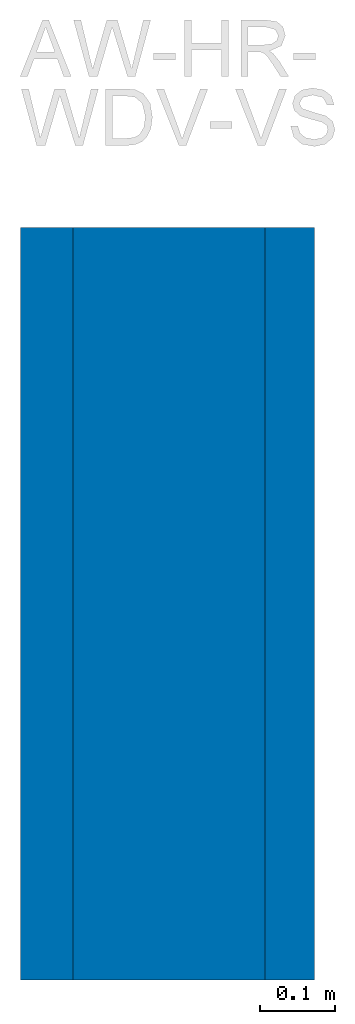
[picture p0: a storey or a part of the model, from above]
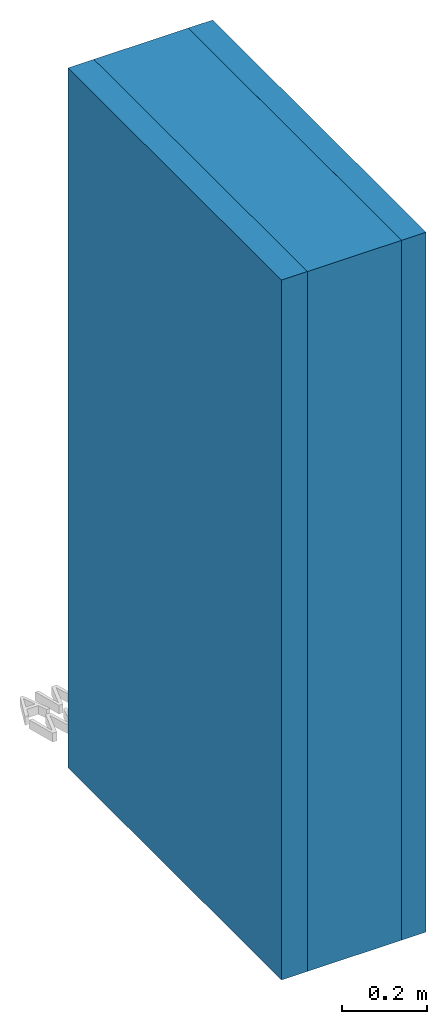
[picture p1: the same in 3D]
Properties of the parts of a building model (IFC4)

# File
Description: ViewDefinition [ReferenceView_V1.2], RevitIdentifiers [VersionGUID: 93d8a1e2-35a5-4253-ab7c-23872298a1db, NumberOfSaves: 0], CoordinateReference [CoordinateBase: Gemeinsam genutzte Koordinaten], ExchangeRequirement [Architecture]
File name: 2018_01
Time: 2023-06-27T14:38:03+01:00
Written by: ODA SDAI 23.12
Made in: Autodesk Revit 24.0.5.432 (DEU) - IFC 24.0.5.432

# IfcProject, 2018_01
Phase: Projekt Status

# IfcSite, Default
RefLatitude: 48, 8, 15, 359802; RefLongitude: 11, 34, 47, 783432; RefElevation: 0 m
Pset_SiteCommon - Reference: Projektinformationen

# IfcBuildingElementProxy: Modelltext:075mm Arial, Modelltext:075mm Arial:2509531
In: Default
Type - Pset_BuildingElementProxyCommon - IsExternal: no
Pset_BuildingElementProxyCommon - Reference: 075mm Arial
Pset_EnvironmentalImpactIndicators - Reference: 075mm Arial
Qto_BuildingElementProxyQuantities - NetSurfaceArea: 0.140851 m2; NetVolume: 0.000451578 m3

# IfcElementAssembly: Wände Baugruppe:fbimSg_Wall_bc_WOD_vis_at_NTR_natuREbuilt_AW-HR-WDV-VS_GK3_39cm, Wände Baugruppe:fbimSg_Wall_bc_WOD_vis_at_NTR_natuREbuilt_AW-HR-WDV-VS_GK3_39cm:2509535
In: Default
PredefinedType: USERDEFINED
Pset_ElementAssemblyCommon - Reference: fbimSg_Wall_bc_WOD_vis_at_NTR_natuREbuilt_AW-HR-WDV-VS_GK3_39cm; sets with these values: 2

# IfcWall: Basiswand:fbimSg_Wall_dp_DRW_vis_at_NTR_natuREbuilt_AWRv-gk_GK3_i_2,5cm, Basiswand:fbimSg_Wall_dp_DRW_vis_at_NTR_natuREbuilt_AWRv-gk_GK3_i_2,5cm:2509534
In: Default
Type - PredefinedType: STANDARD; Material: fbim_16101505_AT_Gipsfaserplatte (2), fbim_14100510_at_NTR_Hanffaserdaemmung, fbim_14153005_AT_001_KlebeArmierspachtel_min
Type - Pset_WallCommon - IsExternal: no
Qto_WallBaseQuantities - fbim_16101505_AT_Gipsfaserplatte, Width: 0.0125 m; fbim_14100510_at_NTR_Hanffaserdaemmung, Width: 0.04 m; fbim_16101505_AT_Gipsfaserplatte (2), Width: 0.0125 m; fbim_14153005_AT_001_KlebeArmierspachtel_min, Width: 0.001 m; Width: 0.066 m; Height: 2 m; Length: 1 m; GrossVolume: 0.132 m3; GrossSideArea: 2 m2; NetSideArea: 2 m2; NetVolume: 0.132 m3
Pset_EnvironmentalImpactIndicators - Reference: fbimSg_Wall_dp_DRW_vis_at_NTR_natuREbuilt_AWRv-gk_GK3_i_2,5cm; sets with these values: 2
Pset_WallCommon - LoadBearing: no; ExtendToStructure: no; Reference: fbimSg_Wall_dp_DRW_vis_at_NTR_natuREbuilt_AWRv-gk_GK3_i_2,5cm

# IfcWall: Basiswand:fbimSg_Wall_dp_INS_vis_at_NTR_natuREbuilt_AWRv-gk_GK3_a_6cm, Basiswand:fbimSg_Wall_dp_INS_vis_at_NTR_natuREbuilt_AWRv-gk_GK3_a_6cm:2509532
In: Default
Type - PredefinedType: STANDARD; Material: fbim_14153515_AT_001_Silikatputz_KP_1.5mm, fbim_14100530_AT_Holzfaserdaemmung
Type - Pset_WallCommon - IsExternal: no
Qto_WallBaseQuantities - fbim_14153515_AT_001_Silikatputz_KP_1.5mm, Width: 0.01 m; fbim_14100530_AT_Holzfaserdaemmung, Width: 0.06 m; Width: 0.07 m; Height: 2 m; Length: 1 m; GrossVolume: 0.14 m3; GrossSideArea: 2 m2; NetSideArea: 2 m2; NetVolume: 0.14 m3
Pset_EnvironmentalImpactIndicators - Reference: fbimSg_Wall_dp_INS_vis_at_NTR_natuREbuilt_AWRv-gk_GK3_a_6cm; sets with these values: 2
Pset_WallCommon - Reference: fbimSg_Wall_dp_INS_vis_at_NTR_natuREbuilt_AWRv-gk_GK3_a_6cm; LoadBearing: no; ExtendToStructure: no

# IfcWall: Basiswand:fbimSg_Wall_sb_WOD_vis_at_NTR_natuREbuilt_AWRv-gk_GK3_k_24cm, Basiswand:fbimSg_Wall_sb_WOD_vis_at_NTR_natuREbuilt_AWRv-gk_GK3_k_24cm:2509533
In: Default
Type - PredefinedType: STANDARD; Material: fbim_14100500_at_NTR_Zellulose-Einblasdaemmung, fbim_12401520_AT_OSB
Type - Pset_WallCommon - IsExternal: no
Qto_WallBaseQuantities - fbim_14100500_at_NTR_Zellulose-Einblasdaemmung, Width: 0.24 m; fbim_12401520_AT_OSB, Width: 0.015 m; Width: 0.255 m; Height: 2 m; Length: 1 m; GrossVolume: 0.51 m3; GrossSideArea: 2 m2; NetSideArea: 2 m2; NetVolume: 0.51 m3
Pset_EnvironmentalImpactIndicators - Reference: fbimSg_Wall_sb_WOD_vis_at_NTR_natuREbuilt_AWRv-gk_GK3_k_24cm; sets with these values: 2
Pset_WallCommon - LoadBearing: no; ExtendToStructure: no; Reference: fbimSg_Wall_sb_WOD_vis_at_NTR_natuREbuilt_AWRv-gk_GK3_k_24cm
